###############################################################
#  Generated by:      Cadence Innovus 21.35-s114_1
#  OS:                Linux x86_64(Host ID pc231.ee.hacettepe.edu.tr)
#  Generated on:      Wed Dec 24 14:09:16 2025
#  Design:            communication_macro
#  Command:           write_lef_abstract -5.7 outputs/communication_macro/communication_macro.lef
###############################################################

VERSION 5.7 ;

BUSBITCHARS "[]" ;
DIVIDERCHAR "/" ;

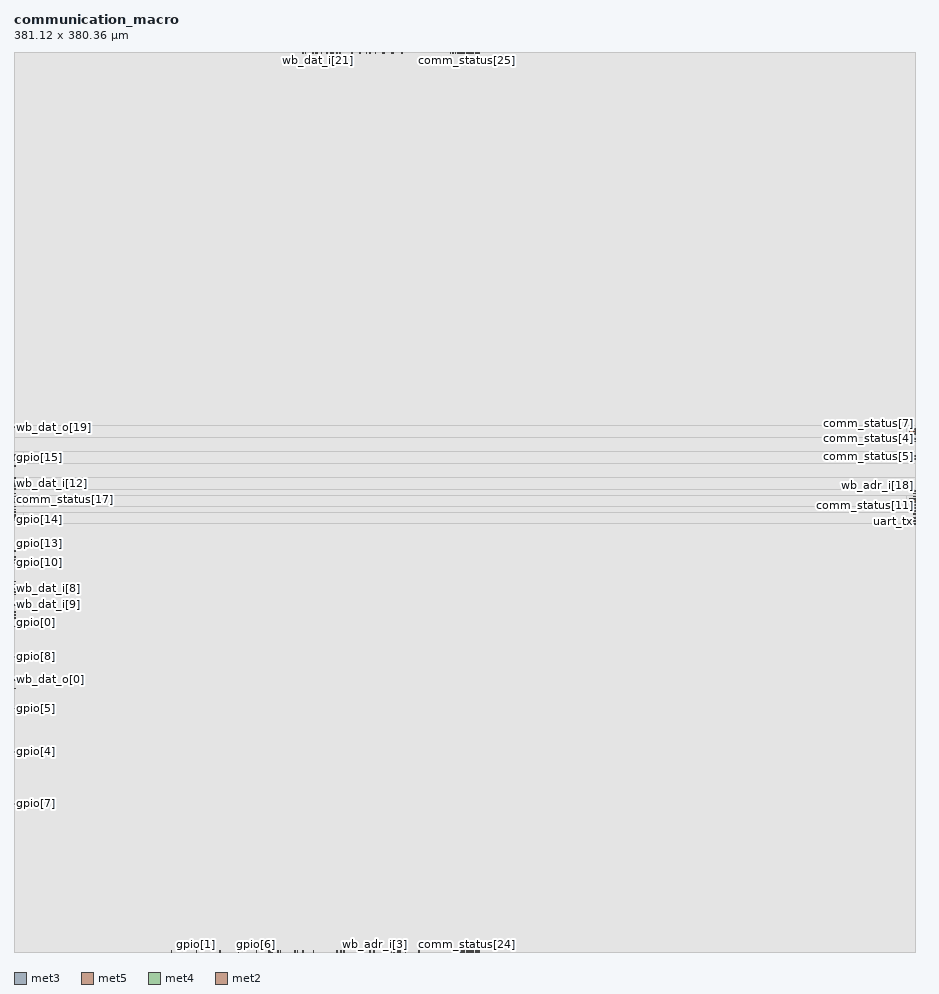
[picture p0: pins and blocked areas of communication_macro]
MACRO communication_macro
  CLASS BLOCK ;
  SIZE 381.120000 BY 380.360000 ;
  FOREIGN communication_macro 0.000000 0.000000 ;
  ORIGIN 0 0 ;
  SYMMETRY X Y R90 ;
  PIN clk
    DIRECTION INPUT ;
    USE SIGNAL ;
    PORT
      LAYER met3 ;
        RECT 0.000000 188.100000 0.800000 188.400000 ;
    END
  END clk
  PIN rst_n
    DIRECTION INPUT ;
    USE SIGNAL ;
    PORT
      LAYER met5 ;
        RECT 0.000000 182.570000 2.500000 184.170000 ;
    END
  END rst_n
  PIN wb_adr_i[31]
    DIRECTION INPUT ;
    USE SIGNAL ;
    PORT
      LAYER met3 ;
        RECT 0.000000 192.370000 0.800000 192.670000 ;
    END
  END wb_adr_i[31]
  PIN wb_adr_i[30]
    DIRECTION INPUT ;
    USE SIGNAL ;
    PORT
      LAYER met3 ;
        RECT 380.320000 192.370000 381.120000 192.670000 ;
    END
  END wb_adr_i[30]
  PIN wb_adr_i[29]
    DIRECTION INPUT ;
    USE SIGNAL ;
    PORT
      LAYER met4 ;
        RECT 187.665000 379.560000 187.965000 380.360000 ;
    END
  END wb_adr_i[29]
  PIN wb_adr_i[28]
    DIRECTION INPUT ;
    USE SIGNAL ;
    PORT
      LAYER met4 ;
        RECT 187.665000 0.000000 187.965000 0.800000 ;
    END
  END wb_adr_i[28]
  PIN wb_adr_i[27]
    DIRECTION INPUT ;
    USE SIGNAL ;
    PORT
      LAYER met3 ;
        RECT 380.320000 187.490000 381.120000 187.790000 ;
    END
  END wb_adr_i[27]
  PIN wb_adr_i[26]
    DIRECTION INPUT ;
    USE SIGNAL ;
    PORT
      LAYER met2 ;
        RECT 187.370000 379.875000 187.510000 380.360000 ;
    END
  END wb_adr_i[26]
  PIN wb_adr_i[25]
    DIRECTION INPUT ;
    USE SIGNAL ;
    PORT
      LAYER met2 ;
        RECT 187.370000 0.000000 187.510000 0.485000 ;
    END
  END wb_adr_i[25]
  PIN wb_adr_i[24]
    DIRECTION INPUT ;
    USE SIGNAL ;
    PORT
      LAYER met2 ;
        RECT 194.090000 379.875000 194.230000 380.360000 ;
    END
  END wb_adr_i[24]
  PIN wb_adr_i[23]
    DIRECTION INPUT ;
    USE SIGNAL ;
    PORT
      LAYER met4 ;
        RECT 193.815000 379.560000 194.115000 380.360000 ;
    END
  END wb_adr_i[23]
  PIN wb_adr_i[22]
    DIRECTION INPUT ;
    USE SIGNAL ;
    PORT
      LAYER met2 ;
        RECT 194.090000 0.000000 194.230000 0.485000 ;
    END
  END wb_adr_i[22]
  PIN wb_adr_i[21]
    DIRECTION INPUT ;
    USE SIGNAL ;
    PORT
      LAYER met4 ;
        RECT 193.815000 0.000000 194.115000 0.800000 ;
    END
  END wb_adr_i[21]
  PIN wb_adr_i[20]
    DIRECTION INPUT ;
    USE SIGNAL ;
    PORT
      LAYER met3 ;
        RECT 0.000000 186.880000 0.800000 187.180000 ;
    END
  END wb_adr_i[20]
  PIN wb_adr_i[19]
    DIRECTION INPUT ;
    USE SIGNAL ;
    PORT
      LAYER met3 ;
        RECT 0.000000 193.590000 0.800000 193.890000 ;
    END
  END wb_adr_i[19]
  PIN wb_adr_i[18]
    DIRECTION INPUT ;
    USE SIGNAL ;
    PORT
      LAYER met3 ;
        RECT 380.320000 193.590000 381.120000 193.890000 ;
    END
  END wb_adr_i[18]
  PIN wb_adr_i[17]
    DIRECTION INPUT ;
    USE SIGNAL ;
    PORT
      LAYER met2 ;
        RECT 186.410000 379.875000 186.550000 380.360000 ;
    END
  END wb_adr_i[17]
  PIN wb_adr_i[16]
    DIRECTION INPUT ;
    USE SIGNAL ;
    PORT
      LAYER met4 ;
        RECT 186.435000 379.560000 186.735000 380.360000 ;
    END
  END wb_adr_i[16]
  PIN wb_adr_i[15]
    DIRECTION INPUT ;
    USE SIGNAL ;
    PORT
      LAYER met2 ;
        RECT 186.410000 0.000000 186.550000 0.485000 ;
    END
  END wb_adr_i[15]
  PIN wb_adr_i[14]
    DIRECTION INPUT ;
    USE SIGNAL ;
    PORT
      LAYER met4 ;
        RECT 186.435000 0.000000 186.735000 0.800000 ;
    END
  END wb_adr_i[14]
  PIN wb_adr_i[13]
    DIRECTION INPUT ;
    USE SIGNAL ;
    PORT
      LAYER met3 ;
        RECT 380.320000 186.270000 381.120000 186.570000 ;
    END
  END wb_adr_i[13]
  PIN wb_adr_i[12]
    DIRECTION INPUT ;
    USE SIGNAL ;
    PORT
      LAYER met2 ;
        RECT 195.050000 379.875000 195.190000 380.360000 ;
    END
  END wb_adr_i[12]
  PIN wb_adr_i[11]
    DIRECTION INPUT ;
    USE SIGNAL ;
    PORT
      LAYER met2 ;
        RECT 195.050000 0.000000 195.190000 0.485000 ;
    END
  END wb_adr_i[11]
  PIN wb_adr_i[10]
    DIRECTION INPUT ;
    USE SIGNAL ;
    PORT
      LAYER met4 ;
        RECT 195.045000 379.560000 195.345000 380.360000 ;
    END
  END wb_adr_i[10]
  PIN wb_adr_i[9]
    DIRECTION INPUT ;
    USE SIGNAL ;
    PORT
      LAYER met2 ;
        RECT 108.170000 0.000000 108.310000 0.485000 ;
    END
  END wb_adr_i[9]
  PIN wb_adr_i[8]
    DIRECTION INPUT ;
    USE SIGNAL ;
    PORT
      LAYER met2 ;
        RECT 109.130000 0.000000 109.270000 0.485000 ;
    END
  END wb_adr_i[8]
  PIN wb_adr_i[7]
    DIRECTION INPUT ;
    USE SIGNAL ;
    PORT
      LAYER met2 ;
        RECT 165.290000 0.000000 165.430000 0.485000 ;
    END
  END wb_adr_i[7]
  PIN wb_adr_i[6]
    DIRECTION INPUT ;
    USE SIGNAL ;
    PORT
      LAYER met2 ;
        RECT 161.930000 0.000000 162.070000 0.485000 ;
    END
  END wb_adr_i[6]
  PIN wb_adr_i[5]
    DIRECTION INPUT ;
    USE SIGNAL ;
    PORT
      LAYER met2 ;
        RECT 163.370000 0.000000 163.510000 0.485000 ;
    END
  END wb_adr_i[5]
  PIN wb_adr_i[4]
    DIRECTION INPUT ;
    USE SIGNAL ;
    PORT
      LAYER met2 ;
        RECT 159.530000 0.000000 159.670000 0.485000 ;
    END
  END wb_adr_i[4]
  PIN wb_adr_i[3]
    DIRECTION INPUT ;
    USE SIGNAL ;
    PORT
      LAYER met2 ;
        RECT 152.330000 0.000000 152.470000 0.485000 ;
    END
  END wb_adr_i[3]
  PIN wb_adr_i[2]
    DIRECTION INPUT ;
    USE SIGNAL ;
    PORT
      LAYER met2 ;
        RECT 148.010000 0.000000 148.150000 0.485000 ;
    END
  END wb_adr_i[2]
  PIN wb_adr_i[1]
    DIRECTION INPUT ;
    USE SIGNAL ;
    PORT
      LAYER met4 ;
        RECT 195.045000 0.000000 195.345000 0.800000 ;
    END
  END wb_adr_i[1]
  PIN wb_adr_i[0]
    DIRECTION INPUT ;
    USE SIGNAL ;
    PORT
      LAYER met3 ;
        RECT 0.000000 185.660000 0.800000 185.960000 ;
    END
  END wb_adr_i[0]
  PIN wb_dat_o[31]
    DIRECTION OUTPUT ;
    USE SIGNAL ;
    PORT
      LAYER met4 ;
        RECT 123.090000 379.560000 123.390000 380.360000 ;
    END
  END wb_dat_o[31]
  PIN wb_dat_o[30]
    DIRECTION OUTPUT ;
    USE SIGNAL ;
    PORT
      LAYER met4 ;
        RECT 126.165000 379.560000 126.465000 380.360000 ;
    END
  END wb_dat_o[30]
  PIN wb_dat_o[29]
    DIRECTION OUTPUT ;
    USE SIGNAL ;
    PORT
      LAYER met4 ;
        RECT 163.680000 379.560000 163.980000 380.360000 ;
    END
  END wb_dat_o[29]
  PIN wb_dat_o[28]
    DIRECTION OUTPUT ;
    USE SIGNAL ;
    PORT
      LAYER met2 ;
        RECT 122.090000 379.875000 122.230000 380.360000 ;
    END
  END wb_dat_o[28]
  PIN wb_dat_o[27]
    DIRECTION OUTPUT ;
    USE SIGNAL ;
    PORT
      LAYER met2 ;
        RECT 150.410000 379.875000 150.550000 380.360000 ;
    END
  END wb_dat_o[27]
  PIN wb_dat_o[26]
    DIRECTION OUTPUT ;
    USE SIGNAL ;
    PORT
      LAYER met2 ;
        RECT 132.170000 379.875000 132.310000 380.360000 ;
    END
  END wb_dat_o[26]
  PIN wb_dat_o[25]
    DIRECTION OUTPUT ;
    USE SIGNAL ;
    PORT
      LAYER met4 ;
        RECT 137.850000 379.560000 138.150000 380.360000 ;
    END
  END wb_dat_o[25]
  PIN wb_dat_o[24]
    DIRECTION OUTPUT ;
    USE SIGNAL ;
    PORT
      LAYER met4 ;
        RECT 134.160000 379.560000 134.460000 380.360000 ;
    END
  END wb_dat_o[24]
  PIN wb_dat_o[23]
    DIRECTION OUTPUT ;
    USE SIGNAL ;
    PORT
      LAYER met2 ;
        RECT 135.050000 379.875000 135.190000 380.360000 ;
    END
  END wb_dat_o[23]
  PIN wb_dat_o[22]
    DIRECTION OUTPUT ;
    USE SIGNAL ;
    PORT
      LAYER met4 ;
        RECT 156.300000 379.560000 156.600000 380.360000 ;
    END
  END wb_dat_o[22]
  PIN wb_dat_o[21]
    DIRECTION OUTPUT ;
    USE SIGNAL ;
    PORT
      LAYER met2 ;
        RECT 136.490000 379.875000 136.630000 380.360000 ;
    END
  END wb_dat_o[21]
  PIN wb_dat_o[20]
    DIRECTION OUTPUT ;
    USE SIGNAL ;
    PORT
      LAYER met2 ;
        RECT 142.730000 379.875000 142.870000 380.360000 ;
    END
  END wb_dat_o[20]
  PIN wb_dat_o[19]
    DIRECTION OUTPUT ;
    USE SIGNAL ;
    PORT
      LAYER met3 ;
        RECT 0.000000 221.650000 0.800000 221.950000 ;
    END
  END wb_dat_o[19]
  PIN wb_dat_o[18]
    DIRECTION OUTPUT ;
    USE SIGNAL ;
    PORT
      LAYER met2 ;
        RECT 148.970000 379.875000 149.110000 380.360000 ;
    END
  END wb_dat_o[18]
  PIN wb_dat_o[17]
    DIRECTION OUTPUT ;
    USE SIGNAL ;
    PORT
      LAYER met3 ;
        RECT 0.000000 205.180000 0.800000 205.480000 ;
    END
  END wb_dat_o[17]
  PIN wb_dat_o[16]
    DIRECTION OUTPUT ;
    USE SIGNAL ;
    PORT
      LAYER met5 ;
        RECT 0.000000 197.210000 2.500000 198.810000 ;
    END
  END wb_dat_o[16]
  PIN wb_dat_o[15]
    DIRECTION OUTPUT ;
    USE SIGNAL ;
    PORT
      LAYER met5 ;
        RECT 0.000000 208.190000 2.500000 209.790000 ;
    END
  END wb_dat_o[15]
  PIN wb_dat_o[14]
    DIRECTION OUTPUT ;
    USE SIGNAL ;
    PORT
      LAYER met3 ;
        RECT 0.000000 199.080000 0.800000 199.380000 ;
    END
  END wb_dat_o[14]
  PIN wb_dat_o[13]
    DIRECTION OUTPUT ;
    USE SIGNAL ;
    PORT
      LAYER met3 ;
        RECT 0.000000 165.530000 0.800000 165.830000 ;
    END
  END wb_dat_o[13]
  PIN wb_dat_o[12]
    DIRECTION OUTPUT ;
    USE SIGNAL ;
    PORT
      LAYER met3 ;
        RECT 0.000000 200.300000 0.800000 200.600000 ;
    END
  END wb_dat_o[12]
  PIN wb_dat_o[11]
    DIRECTION OUTPUT ;
    USE SIGNAL ;
    PORT
      LAYER met3 ;
        RECT 0.000000 141.130000 0.800000 141.430000 ;
    END
  END wb_dat_o[11]
  PIN wb_dat_o[10]
    DIRECTION OUTPUT ;
    USE SIGNAL ;
    PORT
      LAYER met3 ;
        RECT 0.000000 155.160000 0.800000 155.460000 ;
    END
  END wb_dat_o[10]
  PIN wb_dat_o[9]
    DIRECTION OUTPUT ;
    USE SIGNAL ;
    PORT
      LAYER met3 ;
        RECT 0.000000 152.110000 0.800000 152.410000 ;
    END
  END wb_dat_o[9]
  PIN wb_dat_o[8]
    DIRECTION OUTPUT ;
    USE SIGNAL ;
    PORT
      LAYER met3 ;
        RECT 0.000000 150.890000 0.800000 151.190000 ;
    END
  END wb_dat_o[8]
  PIN wb_dat_o[7]
    DIRECTION OUTPUT ;
    USE SIGNAL ;
    PORT
      LAYER met2 ;
        RECT 145.130000 0.000000 145.270000 0.485000 ;
    END
  END wb_dat_o[7]
  PIN wb_dat_o[6]
    DIRECTION OUTPUT ;
    USE SIGNAL ;
    PORT
      LAYER met2 ;
        RECT 160.490000 0.000000 160.630000 0.485000 ;
    END
  END wb_dat_o[6]
  PIN wb_dat_o[5]
    DIRECTION OUTPUT ;
    USE SIGNAL ;
    PORT
      LAYER met2 ;
        RECT 112.490000 0.000000 112.630000 0.485000 ;
    END
  END wb_dat_o[5]
  PIN wb_dat_o[4]
    DIRECTION OUTPUT ;
    USE SIGNAL ;
    PORT
      LAYER met2 ;
        RECT 111.530000 0.000000 111.670000 0.485000 ;
    END
  END wb_dat_o[4]
  PIN wb_dat_o[3]
    DIRECTION OUTPUT ;
    USE SIGNAL ;
    PORT
      LAYER met4 ;
        RECT 162.450000 0.000000 162.750000 0.800000 ;
    END
  END wb_dat_o[3]
  PIN wb_dat_o[2]
    DIRECTION OUTPUT ;
    USE SIGNAL ;
    PORT
      LAYER met2 ;
        RECT 171.050000 0.000000 171.190000 0.485000 ;
    END
  END wb_dat_o[2]
  PIN wb_dat_o[1]
    DIRECTION OUTPUT ;
    USE SIGNAL ;
    PORT
      LAYER met2 ;
        RECT 118.730000 0.000000 118.870000 0.485000 ;
    END
  END wb_dat_o[1]
  PIN wb_dat_o[0]
    DIRECTION OUTPUT ;
    USE SIGNAL ;
    PORT
      LAYER met3 ;
        RECT 0.000000 114.900000 0.800000 115.200000 ;
    END
  END wb_dat_o[0]
  PIN wb_dat_i[31]
    DIRECTION INPUT ;
    USE SIGNAL ;
    PORT
      LAYER met2 ;
        RECT 127.370000 379.875000 127.510000 380.360000 ;
    END
  END wb_dat_i[31]
  PIN wb_dat_i[30]
    DIRECTION INPUT ;
    USE SIGNAL ;
    PORT
      LAYER met2 ;
        RECT 133.610000 379.875000 133.750000 380.360000 ;
    END
  END wb_dat_i[30]
  PIN wb_dat_i[29]
    DIRECTION INPUT ;
    USE SIGNAL ;
    PORT
      LAYER met2 ;
        RECT 163.850000 379.875000 163.990000 380.360000 ;
    END
  END wb_dat_i[29]
  PIN wb_dat_i[28]
    DIRECTION INPUT ;
    USE SIGNAL ;
    PORT
      LAYER met2 ;
        RECT 129.770000 379.875000 129.910000 380.360000 ;
    END
  END wb_dat_i[28]
  PIN wb_dat_i[27]
    DIRECTION INPUT ;
    USE SIGNAL ;
    PORT
      LAYER met2 ;
        RECT 155.690000 379.875000 155.830000 380.360000 ;
    END
  END wb_dat_i[27]
  PIN wb_dat_i[26]
    DIRECTION INPUT ;
    USE SIGNAL ;
    PORT
      LAYER met2 ;
        RECT 126.410000 379.875000 126.550000 380.360000 ;
    END
  END wb_dat_i[26]
  PIN wb_dat_i[25]
    DIRECTION INPUT ;
    USE SIGNAL ;
    PORT
      LAYER met2 ;
        RECT 123.050000 379.875000 123.190000 380.360000 ;
    END
  END wb_dat_i[25]
  PIN wb_dat_i[24]
    DIRECTION INPUT ;
    USE SIGNAL ;
    PORT
      LAYER met2 ;
        RECT 146.090000 379.875000 146.230000 380.360000 ;
    END
  END wb_dat_i[24]
  PIN wb_dat_i[23]
    DIRECTION INPUT ;
    USE SIGNAL ;
    PORT
      LAYER met4 ;
        RECT 127.395000 379.560000 127.695000 380.360000 ;
    END
  END wb_dat_i[23]
  PIN wb_dat_i[22]
    DIRECTION INPUT ;
    USE SIGNAL ;
    PORT
      LAYER met2 ;
        RECT 152.810000 379.875000 152.950000 380.360000 ;
    END
  END wb_dat_i[22]
  PIN wb_dat_i[21]
    DIRECTION INPUT ;
    USE SIGNAL ;
    PORT
      LAYER met2 ;
        RECT 128.330000 379.875000 128.470000 380.360000 ;
    END
  END wb_dat_i[21]
  PIN wb_dat_i[20]
    DIRECTION INPUT ;
    USE SIGNAL ;
    PORT
      LAYER met2 ;
        RECT 137.450000 379.875000 137.590000 380.360000 ;
    END
  END wb_dat_i[20]
  PIN wb_dat_i[19]
    DIRECTION INPUT ;
    USE SIGNAL ;
    PORT
      LAYER met2 ;
        RECT 159.530000 379.875000 159.670000 380.360000 ;
    END
  END wb_dat_i[19]
  PIN wb_dat_i[18]
    DIRECTION INPUT ;
    USE SIGNAL ;
    PORT
      LAYER met4 ;
        RECT 159.990000 379.560000 160.290000 380.360000 ;
    END
  END wb_dat_i[18]
  PIN wb_dat_i[17]
    DIRECTION INPUT ;
    USE SIGNAL ;
    PORT
      LAYER met3 ;
        RECT 0.000000 210.060000 0.800000 210.360000 ;
    END
  END wb_dat_i[17]
  PIN wb_dat_i[16]
    DIRECTION INPUT ;
    USE SIGNAL ;
    PORT
      LAYER met3 ;
        RECT 0.000000 196.640000 0.800000 196.940000 ;
    END
  END wb_dat_i[16]
  PIN wb_dat_i[15]
    DIRECTION INPUT ;
    USE SIGNAL ;
    PORT
      LAYER met3 ;
        RECT 0.000000 207.620000 0.800000 207.920000 ;
    END
  END wb_dat_i[15]
  PIN wb_dat_i[14]
    DIRECTION INPUT ;
    USE SIGNAL ;
    PORT
      LAYER met3 ;
        RECT 0.000000 184.440000 0.800000 184.740000 ;
    END
  END wb_dat_i[14]
  PIN wb_dat_i[13]
    DIRECTION INPUT ;
    USE SIGNAL ;
    PORT
      LAYER met3 ;
        RECT 0.000000 166.750000 0.800000 167.050000 ;
    END
  END wb_dat_i[13]
  PIN wb_dat_i[12]
    DIRECTION INPUT ;
    USE SIGNAL ;
    PORT
      LAYER met3 ;
        RECT 0.000000 197.860000 0.800000 198.160000 ;
    END
  END wb_dat_i[12]
  PIN wb_dat_i[11]
    DIRECTION INPUT ;
    USE SIGNAL ;
    PORT
      LAYER met3 ;
        RECT 0.000000 143.570000 0.800000 143.870000 ;
    END
  END wb_dat_i[11]
  PIN wb_dat_i[10]
    DIRECTION INPUT ;
    USE SIGNAL ;
    PORT
      LAYER met3 ;
        RECT 0.000000 156.380000 0.800000 156.680000 ;
    END
  END wb_dat_i[10]
  PIN wb_dat_i[9]
    DIRECTION INPUT ;
    USE SIGNAL ;
    PORT
      LAYER met3 ;
        RECT 0.000000 146.620000 0.800000 146.920000 ;
    END
  END wb_dat_i[9]
  PIN wb_dat_i[8]
    DIRECTION INPUT ;
    USE SIGNAL ;
    PORT
      LAYER met3 ;
        RECT 0.000000 153.330000 0.800000 153.630000 ;
    END
  END wb_dat_i[8]
  PIN wb_dat_i[7]
    DIRECTION INPUT ;
    USE SIGNAL ;
    PORT
      LAYER met2 ;
        RECT 138.410000 0.000000 138.550000 0.485000 ;
    END
  END wb_dat_i[7]
  PIN wb_dat_i[6]
    DIRECTION INPUT ;
    USE SIGNAL ;
    PORT
      LAYER met2 ;
        RECT 139.370000 0.000000 139.510000 0.485000 ;
    END
  END wb_dat_i[6]
  PIN wb_dat_i[5]
    DIRECTION INPUT ;
    USE SIGNAL ;
    PORT
      LAYER met2 ;
        RECT 126.410000 0.000000 126.550000 0.485000 ;
    END
  END wb_dat_i[5]
  PIN wb_dat_i[4]
    DIRECTION INPUT ;
    USE SIGNAL ;
    PORT
      LAYER met2 ;
        RECT 119.690000 0.000000 119.830000 0.485000 ;
    END
  END wb_dat_i[4]
  PIN wb_dat_i[3]
    DIRECTION INPUT ;
    USE SIGNAL ;
    PORT
      LAYER met2 ;
        RECT 150.410000 0.000000 150.550000 0.485000 ;
    END
  END wb_dat_i[3]
  PIN wb_dat_i[2]
    DIRECTION INPUT ;
    USE SIGNAL ;
    PORT
      LAYER met4 ;
        RECT 151.995000 0.000000 152.295000 0.800000 ;
    END
  END wb_dat_i[2]
  PIN wb_dat_i[1]
    DIRECTION INPUT ;
    USE SIGNAL ;
    PORT
      LAYER met2 ;
        RECT 136.490000 0.000000 136.630000 0.485000 ;
    END
  END wb_dat_i[1]
  PIN wb_dat_i[0]
    DIRECTION INPUT ;
    USE SIGNAL ;
    PORT
      LAYER met2 ;
        RECT 122.090000 0.000000 122.230000 0.485000 ;
    END
  END wb_dat_i[0]
  PIN wb_we_i
    DIRECTION INPUT ;
    USE SIGNAL ;
    PORT
      LAYER met4 ;
        RECT 137.850000 0.000000 138.150000 0.800000 ;
    END
  END wb_we_i
  PIN wb_sel_i[3]
    DIRECTION INPUT ;
    USE SIGNAL ;
    PORT
      LAYER met2 ;
        RECT 185.450000 379.875000 185.590000 380.360000 ;
    END
  END wb_sel_i[3]
  PIN wb_sel_i[2]
    DIRECTION INPUT ;
    USE SIGNAL ;
    PORT
      LAYER met2 ;
        RECT 185.450000 0.000000 185.590000 0.485000 ;
    END
  END wb_sel_i[2]
  PIN wb_sel_i[1]
    DIRECTION INPUT ;
    USE SIGNAL ;
    PORT
      LAYER met3 ;
        RECT 380.320000 194.810000 381.120000 195.110000 ;
    END
  END wb_sel_i[1]
  PIN wb_sel_i[0]
    DIRECTION INPUT ;
    USE SIGNAL ;
    PORT
      LAYER met4 ;
        RECT 185.205000 379.560000 185.505000 380.360000 ;
    END
  END wb_sel_i[0]
  PIN wb_cyc_i
    DIRECTION INPUT ;
    USE SIGNAL ;
    PORT
      LAYER met4 ;
        RECT 107.715000 0.000000 108.015000 0.800000 ;
    END
  END wb_cyc_i
  PIN wb_stb_i
    DIRECTION INPUT ;
    USE SIGNAL ;
    PORT
      LAYER met4 ;
        RECT 108.945000 0.000000 109.245000 0.800000 ;
    END
  END wb_stb_i
  PIN wb_ack_o
    DIRECTION OUTPUT ;
    USE SIGNAL ;
    PORT
      LAYER met2 ;
        RECT 94.730000 0.000000 94.870000 0.485000 ;
    END
  END wb_ack_o
  PIN wb_err_o
    DIRECTION OUTPUT ;
    USE SIGNAL ;
    PORT
      LAYER met4 ;
        RECT 185.205000 0.000000 185.505000 0.800000 ;
    END
  END wb_err_o
  PIN uart_tx
    DIRECTION OUTPUT ;
    USE SIGNAL ;
    PORT
      LAYER met3 ;
        RECT 380.320000 185.050000 381.120000 185.350000 ;
    END
  END uart_tx
  PIN uart_rx
    DIRECTION INPUT ;
    USE SIGNAL ;
    PORT
      LAYER met2 ;
        RECT 196.010000 379.875000 196.150000 380.360000 ;
    END
  END uart_rx
  PIN gpio[15]
    DIRECTION INOUT ;
    USE SIGNAL ;
    PORT
      LAYER met3 ;
        RECT 0.000000 208.840000 0.800000 209.140000 ;
    END
  END gpio[15]
  PIN gpio[14]
    DIRECTION INOUT ;
    USE SIGNAL ;
    PORT
      LAYER met3 ;
        RECT 0.000000 182.610000 0.800000 182.910000 ;
    END
  END gpio[14]
  PIN gpio[13]
    DIRECTION INOUT ;
    USE SIGNAL ;
    PORT
      LAYER met3 ;
        RECT 0.000000 169.190000 0.800000 169.490000 ;
    END
  END gpio[13]
  PIN gpio[12]
    DIRECTION INOUT ;
    USE SIGNAL ;
    PORT
      LAYER met3 ;
        RECT 0.000000 195.420000 0.800000 195.720000 ;
    END
  END gpio[12]
  PIN gpio[11]
    DIRECTION INOUT ;
    USE SIGNAL ;
    PORT
      LAYER met3 ;
        RECT 0.000000 137.470000 0.800000 137.770000 ;
    END
  END gpio[11]
  PIN gpio[10]
    DIRECTION INOUT ;
    USE SIGNAL ;
    PORT
      LAYER met3 ;
        RECT 0.000000 164.310000 0.800000 164.610000 ;
    END
  END gpio[10]
  PIN gpio[9]
    DIRECTION INOUT ;
    USE SIGNAL ;
    PORT
      LAYER met3 ;
        RECT 0.000000 111.240000 0.800000 111.540000 ;
    END
  END gpio[9]
  PIN gpio[8]
    DIRECTION INOUT ;
    USE SIGNAL ;
    PORT
      LAYER met3 ;
        RECT 0.000000 124.660000 0.800000 124.960000 ;
    END
  END gpio[8]
  PIN gpio[7]
    DIRECTION INOUT ;
    USE SIGNAL ;
    PORT
      LAYER met3 ;
        RECT 0.000000 62.440000 0.800000 62.740000 ;
    END
  END gpio[7]
  PIN gpio[6]
    DIRECTION INOUT ;
    USE SIGNAL ;
    PORT
      LAYER met2 ;
        RECT 102.410000 0.000000 102.550000 0.485000 ;
    END
  END gpio[6]
  PIN gpio[5]
    DIRECTION INOUT ;
    USE SIGNAL ;
    PORT
      LAYER met3 ;
        RECT 0.000000 102.700000 0.800000 103.000000 ;
    END
  END gpio[5]
  PIN gpio[4]
    DIRECTION INOUT ;
    USE SIGNAL ;
    PORT
      LAYER met3 ;
        RECT 0.000000 84.400000 0.800000 84.700000 ;
    END
  END gpio[4]
  PIN gpio[3]
    DIRECTION INOUT ;
    USE SIGNAL ;
    PORT
      LAYER met2 ;
        RECT 87.050000 0.000000 87.190000 0.485000 ;
    END
  END gpio[3]
  PIN gpio[2]
    DIRECTION INOUT ;
    USE SIGNAL ;
    PORT
      LAYER met2 ;
        RECT 66.410000 0.000000 66.550000 0.485000 ;
    END
  END gpio[2]
  PIN gpio[1]
    DIRECTION INOUT ;
    USE SIGNAL ;
    PORT
      LAYER met2 ;
        RECT 76.970000 0.000000 77.110000 0.485000 ;
    END
  END gpio[1]
  PIN gpio[0]
    DIRECTION INOUT ;
    USE SIGNAL ;
    PORT
      LAYER met3 ;
        RECT 0.000000 142.350000 0.800000 142.650000 ;
    END
  END gpio[0]
  PIN timer_interrupt
    DIRECTION OUTPUT ;
    USE SIGNAL ;
    PORT
      LAYER met3 ;
        RECT 380.320000 180.780000 381.120000 181.080000 ;
    END
  END timer_interrupt
  PIN timer_compare_out[3]
    DIRECTION OUTPUT ;
    USE SIGNAL ;
    PORT
      LAYER met3 ;
        RECT 380.320000 218.600000 381.120000 218.900000 ;
    END
  END timer_compare_out[3]
  PIN timer_compare_out[2]
    DIRECTION OUTPUT ;
    USE SIGNAL ;
    PORT
      LAYER met3 ;
        RECT 380.320000 221.040000 381.120000 221.340000 ;
    END
  END timer_compare_out[2]
  PIN timer_compare_out[1]
    DIRECTION OUTPUT ;
    USE SIGNAL ;
    PORT
      LAYER met3 ;
        RECT 380.320000 208.230000 381.120000 208.530000 ;
    END
  END timer_compare_out[1]
  PIN timer_compare_out[0]
    DIRECTION OUTPUT ;
    USE SIGNAL ;
    PORT
      LAYER met3 ;
        RECT 380.320000 215.550000 381.120000 215.850000 ;
    END
  END timer_compare_out[0]
  PIN spi_sclk
    DIRECTION OUTPUT ;
    USE SIGNAL ;
    PORT
      LAYER met2 ;
        RECT 196.010000 0.000000 196.150000 0.485000 ;
    END
  END spi_sclk
  PIN spi_mosi
    DIRECTION OUTPUT ;
    USE SIGNAL ;
    PORT
      LAYER met4 ;
        RECT 196.275000 379.560000 196.575000 380.360000 ;
    END
  END spi_mosi
  PIN spi_miso
    DIRECTION INPUT ;
    USE SIGNAL ;
    PORT
      LAYER met4 ;
        RECT 196.275000 0.000000 196.575000 0.800000 ;
    END
  END spi_miso
  PIN spi_cs_n
    DIRECTION OUTPUT ;
    USE SIGNAL ;
    PORT
      LAYER met2 ;
        RECT 184.490000 379.875000 184.630000 380.360000 ;
    END
  END spi_cs_n
  PIN irq
    DIRECTION OUTPUT ;
    USE SIGNAL ;
    PORT
      LAYER met3 ;
        RECT 380.320000 182.000000 381.120000 182.300000 ;
    END
  END irq
  PIN comm_status[31]
    DIRECTION OUTPUT ;
    USE SIGNAL ;
    PORT
      LAYER met2 ;
        RECT 190.250000 379.875000 190.390000 380.360000 ;
    END
  END comm_status[31]
  PIN comm_status[30]
    DIRECTION OUTPUT ;
    USE SIGNAL ;
    PORT
      LAYER met2 ;
        RECT 190.250000 0.000000 190.390000 0.485000 ;
    END
  END comm_status[30]
  PIN comm_status[29]
    DIRECTION OUTPUT ;
    USE SIGNAL ;
    PORT
      LAYER met4 ;
        RECT 190.125000 379.560000 190.425000 380.360000 ;
    END
  END comm_status[29]
  PIN comm_status[28]
    DIRECTION OUTPUT ;
    USE SIGNAL ;
    PORT
      LAYER met4 ;
        RECT 190.125000 0.000000 190.425000 0.800000 ;
    END
  END comm_status[28]
  PIN comm_status[27]
    DIRECTION OUTPUT ;
    USE SIGNAL ;
    PORT
      LAYER met3 ;
        RECT 0.000000 189.930000 0.800000 190.230000 ;
    END
  END comm_status[27]
  PIN comm_status[26]
    DIRECTION OUTPUT ;
    USE SIGNAL ;
    PORT
      LAYER met3 ;
        RECT 380.320000 189.930000 381.120000 190.230000 ;
    END
  END comm_status[26]
  PIN comm_status[25]
    DIRECTION OUTPUT ;
    USE SIGNAL ;
    PORT
      LAYER met2 ;
        RECT 191.210000 379.875000 191.350000 380.360000 ;
    END
  END comm_status[25]
  PIN comm_status[24]
    DIRECTION OUTPUT ;
    USE SIGNAL ;
    PORT
      LAYER met2 ;
        RECT 191.210000 0.000000 191.350000 0.485000 ;
    END
  END comm_status[24]
  PIN comm_status[23]
    DIRECTION OUTPUT ;
    USE SIGNAL ;
    PORT
      LAYER met5 ;
        RECT 0.000000 189.890000 2.500000 191.490000 ;
    END
  END comm_status[23]
  PIN comm_status[22]
    DIRECTION OUTPUT ;
    USE SIGNAL ;
    PORT
      LAYER met5 ;
        RECT 378.620000 189.890000 381.120000 191.490000 ;
    END
  END comm_status[22]
  PIN comm_status[21]
    DIRECTION OUTPUT ;
    USE SIGNAL ;
    PORT
      LAYER met4 ;
        RECT 191.355000 379.560000 191.655000 380.360000 ;
    END
  END comm_status[21]
  PIN comm_status[20]
    DIRECTION OUTPUT ;
    USE SIGNAL ;
    PORT
      LAYER met4 ;
        RECT 191.355000 0.000000 191.655000 0.800000 ;
    END
  END comm_status[20]
  PIN comm_status[19]
    DIRECTION OUTPUT ;
    USE SIGNAL ;
    PORT
      LAYER met2 ;
        RECT 189.290000 379.875000 189.430000 380.360000 ;
    END
  END comm_status[19]
  PIN comm_status[18]
    DIRECTION OUTPUT ;
    USE SIGNAL ;
    PORT
      LAYER met2 ;
        RECT 189.290000 0.000000 189.430000 0.485000 ;
    END
  END comm_status[18]
  PIN comm_status[17]
    DIRECTION OUTPUT ;
    USE SIGNAL ;
    PORT
      LAYER met3 ;
        RECT 0.000000 191.150000 0.800000 191.450000 ;
    END
  END comm_status[17]
  PIN comm_status[16]
    DIRECTION OUTPUT ;
    USE SIGNAL ;
    PORT
      LAYER met3 ;
        RECT 380.320000 191.150000 381.120000 191.450000 ;
    END
  END comm_status[16]
  PIN comm_status[15]
    DIRECTION OUTPUT ;
    USE SIGNAL ;
    PORT
      LAYER met4 ;
        RECT 188.895000 379.560000 189.195000 380.360000 ;
    END
  END comm_status[15]
  PIN comm_status[14]
    DIRECTION OUTPUT ;
    USE SIGNAL ;
    PORT
      LAYER met4 ;
        RECT 188.895000 0.000000 189.195000 0.800000 ;
    END
  END comm_status[14]
  PIN comm_status[13]
    DIRECTION OUTPUT ;
    USE SIGNAL ;
    PORT
      LAYER met2 ;
        RECT 192.170000 379.875000 192.310000 380.360000 ;
    END
  END comm_status[13]
  PIN comm_status[12]
    DIRECTION OUTPUT ;
    USE SIGNAL ;
    PORT
      LAYER met2 ;
        RECT 192.170000 0.000000 192.310000 0.485000 ;
    END
  END comm_status[12]
  PIN comm_status[11]
    DIRECTION OUTPUT ;
    USE SIGNAL ;
    PORT
      LAYER met3 ;
        RECT 380.320000 188.710000 381.120000 189.010000 ;
    END
  END comm_status[11]
  PIN comm_status[10]
    DIRECTION OUTPUT ;
    USE SIGNAL ;
    PORT
      LAYER met3 ;
        RECT 380.320000 183.220000 381.120000 183.520000 ;
    END
  END comm_status[10]
  PIN comm_status[9]
    DIRECTION OUTPUT ;
    USE SIGNAL ;
    PORT
      LAYER met2 ;
        RECT 188.330000 379.875000 188.470000 380.360000 ;
    END
  END comm_status[9]
  PIN comm_status[8]
    DIRECTION OUTPUT ;
    USE SIGNAL ;
    PORT
      LAYER met2 ;
        RECT 188.330000 0.000000 188.470000 0.485000 ;
    END
  END comm_status[8]
  PIN comm_status[7]
    DIRECTION OUTPUT ;
    USE SIGNAL ;
    PORT
      LAYER met3 ;
        RECT 380.320000 219.820000 381.120000 220.120000 ;
    END
  END comm_status[7]
  PIN comm_status[6]
    DIRECTION OUTPUT ;
    USE SIGNAL ;
    PORT
      LAYER met5 ;
        RECT 378.620000 219.170000 381.120000 220.770000 ;
    END
  END comm_status[6]
  PIN comm_status[5]
    DIRECTION OUTPUT ;
    USE SIGNAL ;
    PORT
      LAYER met3 ;
        RECT 380.320000 209.450000 381.120000 209.750000 ;
    END
  END comm_status[5]
  PIN comm_status[4]
    DIRECTION OUTPUT ;
    USE SIGNAL ;
    PORT
      LAYER met3 ;
        RECT 380.320000 216.770000 381.120000 217.070000 ;
    END
  END comm_status[4]
  PIN comm_status[3]
    DIRECTION OUTPUT ;
    USE SIGNAL ;
    PORT
      LAYER met4 ;
        RECT 192.585000 379.560000 192.885000 380.360000 ;
    END
  END comm_status[3]
  PIN comm_status[2]
    DIRECTION OUTPUT ;
    USE SIGNAL ;
    PORT
      LAYER met4 ;
        RECT 192.585000 0.000000 192.885000 0.800000 ;
    END
  END comm_status[2]
  PIN comm_status[1]
    DIRECTION OUTPUT ;
    USE SIGNAL ;
    PORT
      LAYER met2 ;
        RECT 193.130000 379.875000 193.270000 380.360000 ;
    END
  END comm_status[1]
  PIN comm_status[0]
    DIRECTION OUTPUT ;
    USE SIGNAL ;
    PORT
      LAYER met2 ;
        RECT 193.130000 0.000000 193.270000 0.485000 ;
    END
  END comm_status[0]
  OBS
    LAYER met1 ;
      RECT 0.000000 0.000000 381.120000 380.360000 ;
    LAYER met2 ;
      RECT 196.290000 379.735000 381.120000 380.360000 ;
      RECT 195.330000 379.735000 195.870000 380.360000 ;
      RECT 194.370000 379.735000 194.910000 380.360000 ;
      RECT 193.410000 379.735000 193.950000 380.360000 ;
      RECT 192.450000 379.735000 192.990000 380.360000 ;
      RECT 191.490000 379.735000 192.030000 380.360000 ;
      RECT 190.530000 379.735000 191.070000 380.360000 ;
      RECT 189.570000 379.735000 190.110000 380.360000 ;
      RECT 188.610000 379.735000 189.150000 380.360000 ;
      RECT 187.650000 379.735000 188.190000 380.360000 ;
      RECT 186.690000 379.735000 187.230000 380.360000 ;
      RECT 185.730000 379.735000 186.270000 380.360000 ;
      RECT 184.770000 379.735000 185.310000 380.360000 ;
      RECT 164.130000 379.735000 184.350000 380.360000 ;
      RECT 159.810000 379.735000 163.710000 380.360000 ;
      RECT 155.970000 379.735000 159.390000 380.360000 ;
      RECT 153.090000 379.735000 155.550000 380.360000 ;
      RECT 150.690000 379.735000 152.670000 380.360000 ;
      RECT 149.250000 379.735000 150.270000 380.360000 ;
      RECT 146.370000 379.735000 148.830000 380.360000 ;
      RECT 143.010000 379.735000 145.950000 380.360000 ;
      RECT 137.730000 379.735000 142.590000 380.360000 ;
      RECT 136.770000 379.735000 137.310000 380.360000 ;
      RECT 135.330000 379.735000 136.350000 380.360000 ;
      RECT 133.890000 379.735000 134.910000 380.360000 ;
      RECT 132.450000 379.735000 133.470000 380.360000 ;
      RECT 130.050000 379.735000 132.030000 380.360000 ;
      RECT 128.610000 379.735000 129.630000 380.360000 ;
      RECT 127.650000 379.735000 128.190000 380.360000 ;
      RECT 126.690000 379.735000 127.230000 380.360000 ;
      RECT 123.330000 379.735000 126.270000 380.360000 ;
      RECT 122.370000 379.735000 122.910000 380.360000 ;
      RECT 0.000000 379.735000 121.950000 380.360000 ;
      RECT 0.000000 0.625000 381.120000 379.735000 ;
      RECT 196.290000 0.000000 381.120000 0.625000 ;
      RECT 195.330000 0.000000 195.870000 0.625000 ;
      RECT 194.370000 0.000000 194.910000 0.625000 ;
      RECT 193.410000 0.000000 193.950000 0.625000 ;
      RECT 192.450000 0.000000 192.990000 0.625000 ;
      RECT 191.490000 0.000000 192.030000 0.625000 ;
      RECT 190.530000 0.000000 191.070000 0.625000 ;
      RECT 189.570000 0.000000 190.110000 0.625000 ;
      RECT 188.610000 0.000000 189.150000 0.625000 ;
      RECT 187.650000 0.000000 188.190000 0.625000 ;
      RECT 186.690000 0.000000 187.230000 0.625000 ;
      RECT 185.730000 0.000000 186.270000 0.625000 ;
      RECT 171.330000 0.000000 185.310000 0.625000 ;
      RECT 165.570000 0.000000 170.910000 0.625000 ;
      RECT 163.650000 0.000000 165.150000 0.625000 ;
      RECT 162.210000 0.000000 163.230000 0.625000 ;
      RECT 160.770000 0.000000 161.790000 0.625000 ;
      RECT 159.810000 0.000000 160.350000 0.625000 ;
      RECT 152.610000 0.000000 159.390000 0.625000 ;
      RECT 150.690000 0.000000 152.190000 0.625000 ;
      RECT 148.290000 0.000000 150.270000 0.625000 ;
      RECT 145.410000 0.000000 147.870000 0.625000 ;
      RECT 139.650000 0.000000 144.990000 0.625000 ;
      RECT 138.690000 0.000000 139.230000 0.625000 ;
      RECT 136.770000 0.000000 138.270000 0.625000 ;
      RECT 126.690000 0.000000 136.350000 0.625000 ;
      RECT 122.370000 0.000000 126.270000 0.625000 ;
      RECT 119.970000 0.000000 121.950000 0.625000 ;
      RECT 119.010000 0.000000 119.550000 0.625000 ;
      RECT 112.770000 0.000000 118.590000 0.625000 ;
      RECT 111.810000 0.000000 112.350000 0.625000 ;
      RECT 109.410000 0.000000 111.390000 0.625000 ;
      RECT 108.450000 0.000000 108.990000 0.625000 ;
      RECT 102.690000 0.000000 108.030000 0.625000 ;
      RECT 95.010000 0.000000 102.270000 0.625000 ;
      RECT 87.330000 0.000000 94.590000 0.625000 ;
      RECT 77.250000 0.000000 86.910000 0.625000 ;
      RECT 66.690000 0.000000 76.830000 0.625000 ;
      RECT 0.000000 0.000000 66.270000 0.625000 ;
    LAYER met3 ;
      RECT 0.000000 222.250000 381.120000 380.360000 ;
      RECT 1.100000 221.640000 381.120000 222.250000 ;
      RECT 1.100000 221.350000 380.020000 221.640000 ;
      RECT 0.000000 220.740000 380.020000 221.350000 ;
      RECT 0.000000 220.420000 381.120000 220.740000 ;
      RECT 0.000000 219.520000 380.020000 220.420000 ;
      RECT 0.000000 219.200000 381.120000 219.520000 ;
      RECT 0.000000 218.300000 380.020000 219.200000 ;
      RECT 0.000000 217.370000 381.120000 218.300000 ;
      RECT 0.000000 216.470000 380.020000 217.370000 ;
      RECT 0.000000 216.150000 381.120000 216.470000 ;
      RECT 0.000000 215.250000 380.020000 216.150000 ;
      RECT 0.000000 210.660000 381.120000 215.250000 ;
      RECT 1.100000 210.050000 381.120000 210.660000 ;
      RECT 1.100000 209.760000 380.020000 210.050000 ;
      RECT 0.000000 209.440000 380.020000 209.760000 ;
      RECT 1.100000 209.150000 380.020000 209.440000 ;
      RECT 1.100000 208.830000 381.120000 209.150000 ;
      RECT 1.100000 208.540000 380.020000 208.830000 ;
      RECT 0.000000 208.220000 380.020000 208.540000 ;
      RECT 1.100000 207.930000 380.020000 208.220000 ;
      RECT 1.100000 207.320000 381.120000 207.930000 ;
      RECT 0.000000 205.780000 381.120000 207.320000 ;
      RECT 1.100000 204.880000 381.120000 205.780000 ;
      RECT 0.000000 200.900000 381.120000 204.880000 ;
      RECT 1.100000 200.000000 381.120000 200.900000 ;
      RECT 0.000000 199.680000 381.120000 200.000000 ;
      RECT 1.100000 198.780000 381.120000 199.680000 ;
      RECT 0.000000 198.460000 381.120000 198.780000 ;
      RECT 1.100000 197.560000 381.120000 198.460000 ;
      RECT 0.000000 197.240000 381.120000 197.560000 ;
      RECT 1.100000 196.340000 381.120000 197.240000 ;
      RECT 0.000000 196.020000 381.120000 196.340000 ;
      RECT 1.100000 195.410000 381.120000 196.020000 ;
      RECT 1.100000 195.120000 380.020000 195.410000 ;
      RECT 0.000000 194.510000 380.020000 195.120000 ;
      RECT 0.000000 194.190000 381.120000 194.510000 ;
      RECT 1.100000 193.290000 380.020000 194.190000 ;
      RECT 0.000000 192.970000 381.120000 193.290000 ;
      RECT 1.100000 192.070000 380.020000 192.970000 ;
      RECT 0.000000 191.750000 381.120000 192.070000 ;
      RECT 1.100000 190.850000 380.020000 191.750000 ;
      RECT 0.000000 190.530000 381.120000 190.850000 ;
      RECT 1.100000 189.630000 380.020000 190.530000 ;
      RECT 0.000000 189.310000 381.120000 189.630000 ;
      RECT 0.000000 188.700000 380.020000 189.310000 ;
      RECT 1.100000 188.410000 380.020000 188.700000 ;
      RECT 1.100000 188.090000 381.120000 188.410000 ;
      RECT 1.100000 187.800000 380.020000 188.090000 ;
      RECT 0.000000 187.480000 380.020000 187.800000 ;
      RECT 1.100000 187.190000 380.020000 187.480000 ;
      RECT 1.100000 186.870000 381.120000 187.190000 ;
      RECT 1.100000 186.580000 380.020000 186.870000 ;
      RECT 0.000000 186.260000 380.020000 186.580000 ;
      RECT 1.100000 185.970000 380.020000 186.260000 ;
      RECT 1.100000 185.650000 381.120000 185.970000 ;
      RECT 1.100000 185.360000 380.020000 185.650000 ;
      RECT 0.000000 185.040000 380.020000 185.360000 ;
      RECT 1.100000 184.750000 380.020000 185.040000 ;
      RECT 1.100000 184.140000 381.120000 184.750000 ;
      RECT 0.000000 183.820000 381.120000 184.140000 ;
      RECT 0.000000 183.210000 380.020000 183.820000 ;
      RECT 1.100000 182.920000 380.020000 183.210000 ;
      RECT 1.100000 182.600000 381.120000 182.920000 ;
      RECT 1.100000 182.310000 380.020000 182.600000 ;
      RECT 0.000000 181.700000 380.020000 182.310000 ;
      RECT 0.000000 181.380000 381.120000 181.700000 ;
      RECT 0.000000 180.480000 380.020000 181.380000 ;
      RECT 0.000000 169.790000 381.120000 180.480000 ;
      RECT 1.100000 168.890000 381.120000 169.790000 ;
      RECT 0.000000 167.350000 381.120000 168.890000 ;
      RECT 1.100000 166.450000 381.120000 167.350000 ;
      RECT 0.000000 166.130000 381.120000 166.450000 ;
      RECT 1.100000 165.230000 381.120000 166.130000 ;
      RECT 0.000000 164.910000 381.120000 165.230000 ;
      RECT 1.100000 164.010000 381.120000 164.910000 ;
      RECT 0.000000 156.980000 381.120000 164.010000 ;
      RECT 1.100000 156.080000 381.120000 156.980000 ;
      RECT 0.000000 155.760000 381.120000 156.080000 ;
      RECT 1.100000 154.860000 381.120000 155.760000 ;
      RECT 0.000000 153.930000 381.120000 154.860000 ;
      RECT 1.100000 153.030000 381.120000 153.930000 ;
      RECT 0.000000 152.710000 381.120000 153.030000 ;
      RECT 1.100000 151.810000 381.120000 152.710000 ;
      RECT 0.000000 151.490000 381.120000 151.810000 ;
      RECT 1.100000 150.590000 381.120000 151.490000 ;
      RECT 0.000000 147.220000 381.120000 150.590000 ;
      RECT 1.100000 146.320000 381.120000 147.220000 ;
      RECT 0.000000 144.170000 381.120000 146.320000 ;
      RECT 1.100000 143.270000 381.120000 144.170000 ;
      RECT 0.000000 142.950000 381.120000 143.270000 ;
      RECT 1.100000 142.050000 381.120000 142.950000 ;
      RECT 0.000000 141.730000 381.120000 142.050000 ;
      RECT 1.100000 140.830000 381.120000 141.730000 ;
      RECT 0.000000 138.070000 381.120000 140.830000 ;
      RECT 1.100000 137.170000 381.120000 138.070000 ;
      RECT 0.000000 125.260000 381.120000 137.170000 ;
      RECT 1.100000 124.360000 381.120000 125.260000 ;
      RECT 0.000000 115.500000 381.120000 124.360000 ;
      RECT 1.100000 114.600000 381.120000 115.500000 ;
      RECT 0.000000 111.840000 381.120000 114.600000 ;
      RECT 1.100000 110.940000 381.120000 111.840000 ;
      RECT 0.000000 103.300000 381.120000 110.940000 ;
      RECT 1.100000 102.400000 381.120000 103.300000 ;
      RECT 0.000000 85.000000 381.120000 102.400000 ;
      RECT 1.100000 84.100000 381.120000 85.000000 ;
      RECT 0.000000 63.040000 381.120000 84.100000 ;
      RECT 1.100000 62.140000 381.120000 63.040000 ;
      RECT 0.000000 0.000000 381.120000 62.140000 ;
    LAYER met4 ;
      RECT 196.875000 379.260000 381.120000 380.360000 ;
      RECT 195.645000 379.260000 195.975000 380.360000 ;
      RECT 194.415000 379.260000 194.745000 380.360000 ;
      RECT 193.185000 379.260000 193.515000 380.360000 ;
      RECT 191.955000 379.260000 192.285000 380.360000 ;
      RECT 190.725000 379.260000 191.055000 380.360000 ;
      RECT 189.495000 379.260000 189.825000 380.360000 ;
      RECT 188.265000 379.260000 188.595000 380.360000 ;
      RECT 187.035000 379.260000 187.365000 380.360000 ;
      RECT 185.805000 379.260000 186.135000 380.360000 ;
      RECT 164.280000 379.260000 184.905000 380.360000 ;
      RECT 160.590000 379.260000 163.380000 380.360000 ;
      RECT 156.900000 379.260000 159.690000 380.360000 ;
      RECT 138.450000 379.260000 156.000000 380.360000 ;
      RECT 134.760000 379.260000 137.550000 380.360000 ;
      RECT 127.995000 379.260000 133.860000 380.360000 ;
      RECT 126.765000 379.260000 127.095000 380.360000 ;
      RECT 123.690000 379.260000 125.865000 380.360000 ;
      RECT 0.000000 379.260000 122.790000 380.360000 ;
      RECT 0.000000 1.100000 381.120000 379.260000 ;
      RECT 196.875000 0.000000 381.120000 1.100000 ;
      RECT 195.645000 0.000000 195.975000 1.100000 ;
      RECT 194.415000 0.000000 194.745000 1.100000 ;
      RECT 193.185000 0.000000 193.515000 1.100000 ;
      RECT 191.955000 0.000000 192.285000 1.100000 ;
      RECT 190.725000 0.000000 191.055000 1.100000 ;
      RECT 189.495000 0.000000 189.825000 1.100000 ;
      RECT 188.265000 0.000000 188.595000 1.100000 ;
      RECT 187.035000 0.000000 187.365000 1.100000 ;
      RECT 185.805000 0.000000 186.135000 1.100000 ;
      RECT 163.050000 0.000000 184.905000 1.100000 ;
      RECT 152.595000 0.000000 162.150000 1.100000 ;
      RECT 138.450000 0.000000 151.695000 1.100000 ;
      RECT 109.545000 0.000000 137.550000 1.100000 ;
      RECT 108.315000 0.000000 108.645000 1.100000 ;
      RECT 0.000000 0.000000 107.415000 1.100000 ;
    LAYER met5 ;
      RECT 0.000000 222.370000 381.120000 380.360000 ;
      RECT 0.000000 217.570000 377.020000 222.370000 ;
      RECT 0.000000 211.390000 381.120000 217.570000 ;
      RECT 4.100000 206.590000 381.120000 211.390000 ;
      RECT 0.000000 200.410000 381.120000 206.590000 ;
      RECT 4.100000 195.610000 381.120000 200.410000 ;
      RECT 0.000000 193.090000 381.120000 195.610000 ;
      RECT 4.100000 188.290000 377.020000 193.090000 ;
      RECT 0.000000 185.770000 381.120000 188.290000 ;
      RECT 4.100000 180.970000 381.120000 185.770000 ;
      RECT 0.000000 0.000000 381.120000 180.970000 ;
  END
END communication_macro

END LIBRARY
